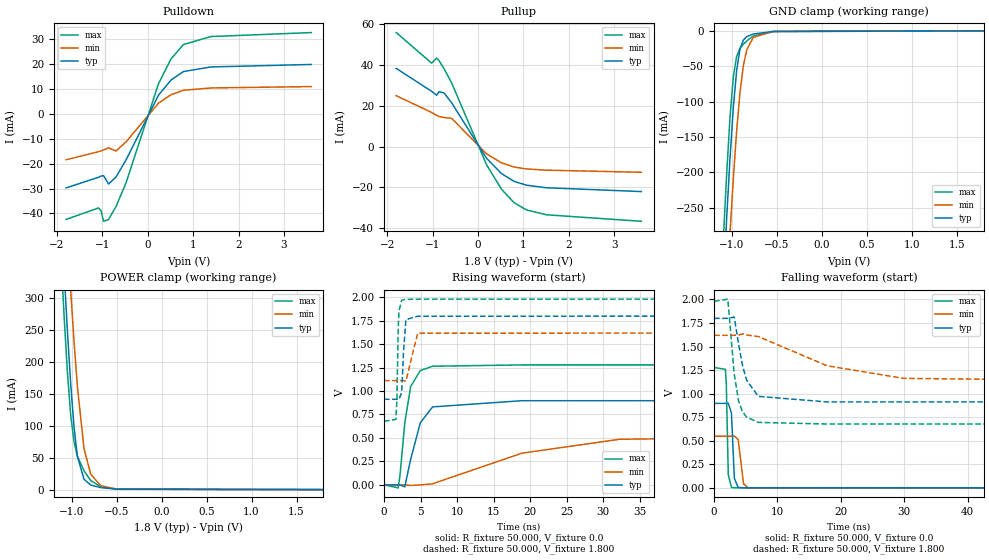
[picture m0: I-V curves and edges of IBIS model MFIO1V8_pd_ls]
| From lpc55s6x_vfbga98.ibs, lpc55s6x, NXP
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|   Model MFIO1V8_pd_ls
[Model] MFIO1V8_pd_ls
Model_type I/O
Polarity   Non-Inverting
Enable   Active-Low
Vinl =  0.540V
Vinh =  1.260V
Vmeas =  0.900V
Cref =  0.0F
Rref =  100.000
Vref =  0.0V
C_comp   2.019pF   1.989pF   2.027pF
C_comp_pullup   1.198pF   1.161pF   1.230pF
C_comp_pulldown   0.670pF   0.640pF   0.684pF
[Model Spec]
Vinh   1.260V   1.134V   1.386V
Vinl   0.540V   0.486V   0.594V
Vmeas   0.900V   0.810V   0.990V
Vref   0.0V   0.0V   0.0V
Cref   0.0F   0.0F   0.0F
Rref   100.000   100.000   100.000
[Temperature Range]   25.000   0.125k   -40.000
[Voltage Range]   1.800V   1.620V   1.980V
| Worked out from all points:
|   slope of the pulldown table from 0 to 0.27 V, typ, clamps not added: 32.2 ohm
|   slope of the pullup table from 0 to 0.27 V, typ, clamps not added: 34.3 ohm
|   GND clamp passes 1 mA (typ) near -0.56 V on its own axis
|   POWER clamp passes 1 mA (typ) near -0.54 V on its own axis
|   rising waveform, R_fixture 50.000, V_fixture 0.0: 20-80 % time 1.89ns typ, 15.8ns min, 1.21ns max; typ from 0 V to 0.897 V
|   rising waveform, R_fixture 50.000, V_fixture 1.800: 20-80 % time 276ps typ, 400ps min, 194ps max; typ from 0.912 V to 1.8 V
|   falling waveform, R_fixture 50.000, V_fixture 0.0: 20-80 % time 315ps typ, 493ps min, 217ps max; typ from 0.897 V to 0 V
|   falling waveform, R_fixture 50.000, V_fixture 1.800: 20-80 % time 1.84ns typ, 13.6ns min, 1.28ns max; typ from 1.8 V to 0.912 V
[Pulldown]
|Voltage   I(typ)   I(min)   I(max)
-1.8V     -29.75mA   -18.45mA   -42.39mA
-1.085V   -25.48mA   -15.2mA    -37.79mA
-1.03V    -24.99mA   -14.87mA   -38.88mA
-975mV    -24.83mA   -14.51mA   -43.15mA
-865mV    -28.18mA   -13.68mA   -42.43mA
-700mV    -25.38mA   -14.92mA   -37.23mA
-480mV    -18.54mA   -11.29mA   -27.73mA
235mV     7.474mA    4.265mA    12.03mA
510mV     13.55mA    7.648mA    22.01mA
785mV     16.96mA    9.446mA    27.8mA
1.39V     18.81mA    10.38mA    31.01mA
3.6V      19.8mA     10.93mA    32.61mA
[Pullup]
|Voltage   I(typ)   I(min)   I(max)
-1.8V     38.29mA    24.9mA     55.82mA
-1.02V    27.05mA    16.71mA    40.87mA
-910mV    25.14mA    15.31mA    43.32mA
-855mV    26.89mA    14.69mA    42.04mA
-745mV    26.24mA    14.22mA    38.06mA
-580mV    21.45mA    13.82mA    31.22mA
190mV     -5.761mA   -3.564mA   -8.914mA
520mV     -13.24mA   -7.997mA   -20.92mA
795mV     -17.02mA   -10.03mA   -27.47mA
1.07V     -18.92mA   -10.95mA   -31.04mA
1.51V     -20.18mA   -11.56mA   -33.41mA
3.6V      -22.04mA   -12.6mA    -36.6mA
[GND_clamp]
|Voltage   I(typ)   I(min)   I(max)
-1.8V     -2.463A    -2.494A    -2.446A
-1.097V   -357.7mA   -460.7mA   -294.8mA
-1.06V    -264.9mA   -370.9mA   -202.5mA
-1.023V   -180.4mA   -286.3mA   -122.9mA
-986mV    -108.7mA   -208.9mA   -65.05mA
-949mV    -56.06mA   -141.4mA   -36.24mA
-912mV    -25.87mA   -87.65mA   -25.01mA
-875mV    -13.21mA   -49.99mA   -19.06mA
-838mV    -8.315mA   -27.44mA   -14.52mA
-764mV    -4.558mA   -9.219mA   -7.395mA
-542mV    -813.9uA   -810.7uA   -1.086mA
1.8V      0A         0A         0A
[POWER_clamp]
|Voltage   I(typ)   I(min)   I(max)
-1.8V     2.577A     2.626A     2.553A
-1.123V   442.8mA    582.7mA    371.8mA
-1.086V   342mA      487.8mA    272.2mA
-1.049V   248.2mA    396.7mA    184.1mA
-1.012V   164.7mA    310.5mA    115.9mA
-975mV    97.4mA     231.2mA    74.47mA
-938mV    52.21mA    161.5mA    52.2mA
-864mV    16.15mA    64.06mA    29.43mA
-790mV    7.073mA    24.26mA    14.23mA
-679mV    3.152mA    6.087mA    4.407mA
-494mV    590.1uA    655.5uA    758.5uA
1.8V      0A         0A         0A
[Ramp]
| variable   typ   min   max
dV/dt_r   0.538/1.890n   0.328/15.774n   0.767/1.209n
dV/dt_f   0.532/1.835n   0.305/13.602n   0.781/1.275n
R_load = 50.000
[Rising Waveform]
R_fixture= 50.000
V_fixture= 0.0
V_fixture_min= 0.0
V_fixture_max= 0.0
|time   V(typ)   V(min)   V(max)
0s        6.721nV    117.6nV    4.416nV
1.96ns    159.2uV    49.14nV    -31.69mV
2.19ns    -99uV      -10.76uV   100.6mV
2.85ns    -21.07mV   112uV      661mV
3.65ns    271.3mV    -6.136mV   1.047V
4.97ns    661.3mV    -816.4uV   1.218V
6.65ns    830.9mV    11.84mV    1.264V
18.84ns   896.7mV    337.2mV    1.278V
32.24ns   896.7mV    486.1mV    1.278V
100ns     896.7mV    547.3mV    1.278V
[Rising Waveform]
R_fixture= 50.000
V_fixture= 1.800
V_fixture_min= 1.620
V_fixture_max= 1.980
|time   V(typ)   V(min)   V(max)
0s        911.9mV    1.111V     677.7mV
1.63ns    911.9mV    1.111V     697.7mV
1.77ns    912.1mV    1.111V     900.3mV
1.95ns    911.4mV    1.111V     1.665V
2.05ns    909.6mV    1.111V     1.849V
2.42ns    983.6mV    1.111V     1.967V
2.68ns    1.419V     1.11V      1.973V
3ns       1.76V      1.107V     1.976V
4.61ns    1.797V     1.616V     1.979V
100ns     1.799V     1.619V     1.979V
[Falling Waveform]
R_fixture= 50.000
V_fixture= 0.0
V_fixture_min= 0.0
V_fixture_max= 0.0
|time   V(typ)   V(min)   V(max)
0s        896.7mV    547.4mV    1.278V
1.79ns    896.7mV    547.4mV    1.258V
1.93ns    896.6mV    547.4mV    1.106V
2.24ns    898.4mV    547.4mV    142.2mV
2.74ns    796.7mV    547.3mV    4.509mV
3.2ns     100.7mV    549.7mV    1.658mV
3.81ns    3.552mV    513mV      778.9uV
4.65ns    1.171mV    43.83mV    345.8uV
5.32ns    655.7uV    1.786mV    189.7uV
100ns     14.3nV     184.2nV    8.877nV
[Falling Waveform]
R_fixture= 50.000
V_fixture= 1.800
V_fixture_min= 1.620
V_fixture_max= 1.980
|time   V(typ)   V(min)   V(max)
0s        1.799V     1.619V     1.979V
2.17ns    1.799V     1.619V     2.003V
3.18ns    1.813V     1.619V     1.21V
3.88ns    1.522V     1.623V     915.7mV
4.5ns     1.295V     1.633V     807.3mV
5.16ns    1.14V      1.622V     750mV
6.98ns    971mV      1.606V     694.9mV
17.82ns   912mV      1.296V     677.7mV
29.92ns   911.9mV    1.162V     677.7mV
100ns     911.9mV    1.111V     677.7mV
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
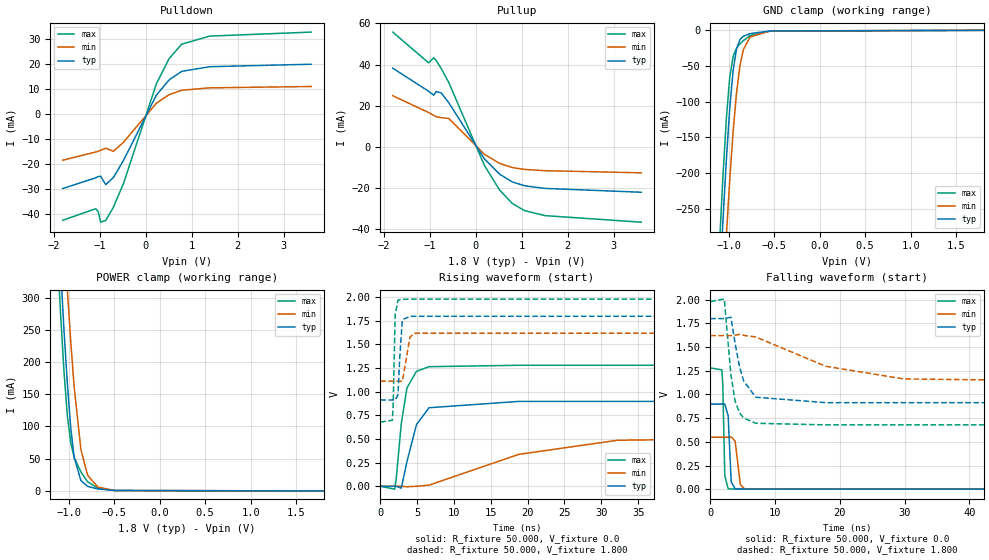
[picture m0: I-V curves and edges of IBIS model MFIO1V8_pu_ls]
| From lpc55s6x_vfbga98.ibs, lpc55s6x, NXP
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|   Model MFIO1V8_pu_ls
[Model] MFIO1V8_pu_ls
Model_type I/O
Polarity   Non-Inverting
Enable   Active-Low
Vinl =  0.540V
Vinh =  1.260V
Vmeas =  0.900V
Cref =  0.0F
Rref =  100.000
Vref =  0.0V
C_comp   2.019pF   1.989pF   2.027pF
C_comp_pullup   1.197pF   1.159pF   1.228pF
C_comp_pulldown   0.671pF   0.642pF   0.686pF
[Model Spec]
Vinh   1.260V   1.134V   1.386V
Vinl   0.540V   0.486V   0.594V
Vmeas   0.900V   0.810V   0.990V
Vref   0.0V   0.0V   0.0V
Cref   0.0F   0.0F   0.0F
Rref   100.000   100.000   100.000
[Temperature Range]   25.000   0.125k   -40.000
[Voltage Range]   1.800V   1.620V   1.980V
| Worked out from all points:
|   slope of the pulldown table from 0 to 0.27 V, typ, clamps not added: 32.2 ohm
|   slope of the pullup table from 0 to 0.27 V, typ, clamps not added: 34.3 ohm
|   GND clamp passes 1 mA (typ) near -0.56 V on its own axis
|   POWER clamp passes 1 mA (typ) near -0.54 V on its own axis
|   rising waveform, R_fixture 50.000, V_fixture 0.0: 20-80 % time 1.89ns typ, 15.8ns min, 1.21ns max; typ from 0.001 V to 0.898 V
|   rising waveform, R_fixture 50.000, V_fixture 1.800: 20-80 % time 275ps typ, 401ps min, 197ps max; typ from 0.913 V to 1.8 V
|   falling waveform, R_fixture 50.000, V_fixture 0.0: 20-80 % time 314ps typ, 502ps min, 216ps max; typ from 0.898 V to 0.001 V
|   falling waveform, R_fixture 50.000, V_fixture 1.800: 20-80 % time 1.84ns typ, 13.6ns min, 1.27ns max; typ from 1.8 V to 0.913 V
[Pulldown]
|Voltage   I(typ)   I(min)   I(max)
-1.8V     -29.75mA   -18.45mA   -42.39mA
-1.085V   -25.48mA   -15.2mA    -37.79mA
-1.03V    -24.99mA   -14.87mA   -38.88mA
-975mV    -24.83mA   -14.51mA   -43.15mA
-865mV    -28.18mA   -13.68mA   -42.43mA
-700mV    -25.38mA   -14.92mA   -37.23mA
-480mV    -18.54mA   -11.29mA   -27.73mA
235mV     7.474mA    4.265mA    12.03mA
510mV     13.55mA    7.648mA    22.01mA
785mV     16.96mA    9.446mA    27.8mA
1.39V     18.81mA    10.38mA    31.01mA
3.6V      19.8mA     10.93mA    32.61mA
[Pullup]
|Voltage   I(typ)   I(min)   I(max)
-1.8V     38.29mA    24.9mA     55.82mA
-1.02V    27.05mA    16.71mA    40.87mA
-910mV    25.14mA    15.31mA    43.32mA
-855mV    26.89mA    14.69mA    42.04mA
-745mV    26.24mA    14.22mA    38.06mA
-580mV    21.45mA    13.82mA    31.22mA
190mV     -5.761mA   -3.564mA   -8.914mA
520mV     -13.24mA   -7.997mA   -20.92mA
795mV     -17.02mA   -10.03mA   -27.47mA
1.07V     -18.92mA   -10.95mA   -31.04mA
1.51V     -20.18mA   -11.56mA   -33.41mA
3.6V      -22.04mA   -12.6mA    -36.6mA
[GND_clamp]
|Voltage   I(typ)   I(min)   I(max)
-1.8V     -2.463A    -2.494A    -2.446A
-1.097V   -357.7mA   -460.7mA   -294.9mA
-1.06V    -264.9mA   -371mA     -202.6mA
-1.023V   -180.4mA   -286.4mA   -122.9mA
-986mV    -108.7mA   -208.9mA   -65.09mA
-949mV    -56.09mA   -141.5mA   -36.28mA
-912mV    -25.91mA   -87.68mA   -25.06mA
-875mV    -13.24mA   -50.02mA   -19.11mA
-838mV    -8.35mA    -27.47mA   -14.57mA
-764mV    -4.593mA   -9.247mA   -7.441mA
-542mV    -849.5uA   -838.5uA   -1.132mA
1.8V      0A         0A         0A
[POWER_clamp]
|Voltage   I(typ)   I(min)   I(max)
-1.8V     2.577A     2.626A     2.553A
-1.123V   442.8mA    582.7mA    371.7mA
-1.086V   342mA      487.8mA    272.2mA
-1.049V   248.2mA    396.7mA    184.1mA
-1.012V   164.7mA    310.5mA    115.9mA
-975mV    97.36mA    231.1mA    74.42mA
-938mV    52.18mA    161.5mA    52.15mA
-864mV    16.11mA    64.03mA    29.39mA
-790mV    7.037mA    24.23mA    14.18mA
-679mV    3.116mA    6.059mA    4.361mA
-494mV    554.4uA    627.7uA    712.3uA
1.8V      0A         0A         0A
[Ramp]
| variable   typ   min   max
dV/dt_r   0.538/1.890n   0.329/15.774n   0.767/1.208n
dV/dt_f   0.532/1.835n   0.305/13.603n   0.781/1.276n
R_load = 50.000
[Rising Waveform]
R_fixture= 50.000
V_fixture= 0.0
V_fixture_min= 0.0
V_fixture_max= 0.0
|time   V(typ)   V(min)   V(max)
0s        630.6uV    679.1uV    587.5uV
1.96ns    789.2uV    679uV      -30.05mV
2.17ns    646.8uV    675.9uV    85.5mV
2.85ns    -19.7mV    790uV      661.1mV
3.62ns    261mV      -4.771mV   1.04V
4.91ns    652mV      527.3uV    1.216V
6.62ns    831mV      12.71mV    1.265V
18.81ns   898mV      338mV      1.28V
32.21ns   898mV      487.2mV    1.28V
100ns     898mV      548.5mV    1.28V
[Rising Waveform]
R_fixture= 50.000
V_fixture= 1.800
V_fixture_min= 1.620
V_fixture_max= 1.980
|time   V(typ)   V(min)   V(max)
0s        913.3mV    1.112V     678.9mV
1.63ns    913.3mV    1.112V     698.4mV
1.75ns    913.5mV    1.112V     853.9mV
2.02ns    911.7mV    1.112V     1.814V
2.4ns     967.4mV    1.112V     1.968V
2.67ns    1.397V     1.112V     1.974V
3ns       1.762V     1.109V     1.977V
4.03ns    1.797V     1.578V     1.979V
4.64ns    1.798V     1.618V     1.979V
100ns     1.8V       1.62V      1.98V
[Falling Waveform]
R_fixture= 50.000
V_fixture= 0.0
V_fixture_min= 0.0
V_fixture_max= 0.0
|time   V(typ)   V(min)   V(max)
0s        898mV      548.7mV    1.28V
1.79ns    898mV      548.7mV    1.259V
1.93ns    897.9mV    548.6mV    1.108V
2.24ns    899.8mV    548.7mV    143.9mV
2.76ns    775.9mV    548.5mV    5.275mV
3.23ns    78.56mV    551.3mV    2.369mV
3.84ns    4.35mV     507.6mV    1.439mV
4.64ns    1.976mV    49.12mV    976.3uV
5.28ns    1.396mV    3.386mV    806.1uV
100ns     630.7uV    679.2uV    587.5uV
[Falling Waveform]
R_fixture= 50.000
V_fixture= 1.800
V_fixture_min= 1.620
V_fixture_max= 1.980
|time   V(typ)   V(min)   V(max)
0s        1.8V       1.62V      1.98V
2.16ns    1.8V       1.62V      2.006V
3.18ns    1.814V     1.62V      1.212V
3.84ns    1.538V     1.623V     928.3mV
4.5ns     1.297V     1.634V     808mV
5.16ns    1.142V     1.623V     751.1mV
7.03ns    970.5mV    1.606V     695.5mV
17.83ns   913.4mV    1.297V     678.9mV
29.93ns   913.3mV    1.163V     678.9mV
100ns     913.3mV    1.112V     678.9mV
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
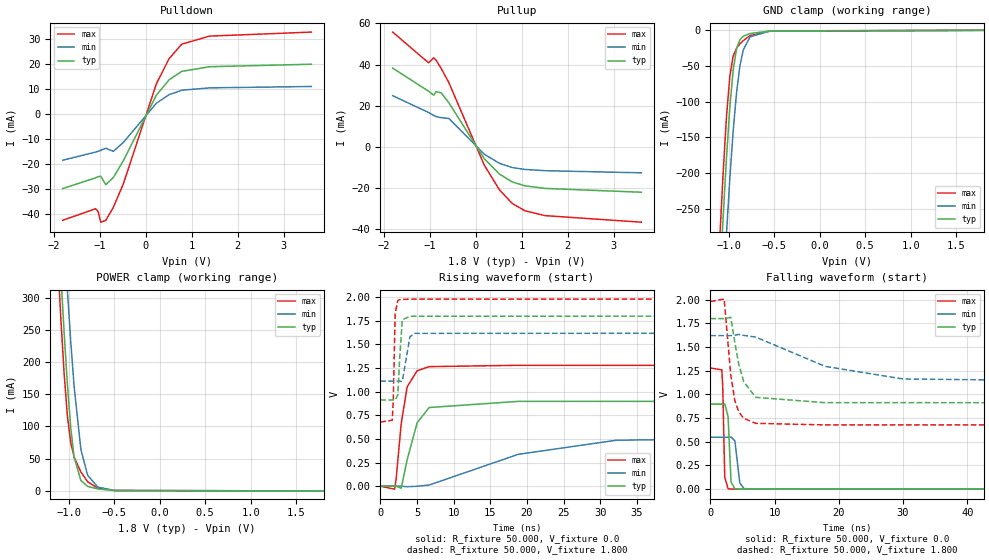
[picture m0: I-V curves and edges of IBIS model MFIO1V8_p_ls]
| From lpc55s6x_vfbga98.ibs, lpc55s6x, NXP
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|   Model MFIO1V8_p_ls
[Model] MFIO1V8_p_ls
Model_type I/O
Polarity   Non-Inverting
Enable   Active-Low
Vinl =  0.540V
Vinh =  1.260V
Vmeas =  0.900V
Cref =  0.0F
Rref =  100.000
Vref =  0.0V
C_comp   2.019pF   1.989pF   2.027pF
C_comp_pullup   1.197pF   1.160pF   1.229pF
C_comp_pulldown   0.671pF   0.641pF   0.686pF
[Model Spec]
Vinh   1.260V   1.134V   1.386V
Vinl   0.540V   0.486V   0.594V
Vmeas   0.900V   0.810V   0.990V
Vref   0.0V   0.0V   0.0V
Cref   0.0F   0.0F   0.0F
Rref   100.000   100.000   100.000
[Temperature Range]   25.000   0.125k   -40.000
[Voltage Range]   1.800V   1.620V   1.980V
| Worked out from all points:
|   slope of the pulldown table from 0 to 0.27 V, typ, clamps not added: 32.2 ohm
|   slope of the pullup table from 0 to 0.27 V, typ, clamps not added: 34.3 ohm
|   GND clamp passes 1 mA (typ) near -0.56 V on its own axis
|   POWER clamp passes 1 mA (typ) near -0.54 V on its own axis
|   rising waveform, R_fixture 50.000, V_fixture 0.0: 20-80 % time 1.89ns typ, 15.8ns min, 1.21ns max; typ from 0 V to 0.897 V
|   rising waveform, R_fixture 50.000, V_fixture 1.800: 20-80 % time 278ps typ, 404ps min, 192ps max; typ from 0.913 V to 1.8 V
|   falling waveform, R_fixture 50.000, V_fixture 0.0: 20-80 % time 314ps typ, 498ps min, 221ps max; typ from 0.897 V to 0 V
|   falling waveform, R_fixture 50.000, V_fixture 1.800: 20-80 % time 1.84ns typ, 13.6ns min, 1.28ns max; typ from 1.8 V to 0.913 V
[Pulldown]
|Voltage   I(typ)   I(min)   I(max)
-1.8V     -29.75mA   -18.45mA   -42.39mA
-1.085V   -25.48mA   -15.2mA    -37.79mA
-1.03V    -24.99mA   -14.87mA   -38.88mA
-975mV    -24.83mA   -14.51mA   -43.15mA
-865mV    -28.18mA   -13.68mA   -42.43mA
-700mV    -25.38mA   -14.92mA   -37.23mA
-480mV    -18.54mA   -11.29mA   -27.73mA
235mV     7.474mA    4.265mA    12.03mA
510mV     13.55mA    7.648mA    22.01mA
785mV     16.96mA    9.446mA    27.8mA
1.39V     18.81mA    10.38mA    31.01mA
3.6V      19.8mA     10.93mA    32.61mA
[Pullup]
|Voltage   I(typ)   I(min)   I(max)
-1.8V     38.29mA    24.9mA     55.82mA
-1.02V    27.05mA    16.71mA    40.87mA
-910mV    25.14mA    15.31mA    43.32mA
-855mV    26.89mA    14.69mA    42.04mA
-745mV    26.24mA    14.22mA    38.06mA
-580mV    21.45mA    13.82mA    31.22mA
190mV     -5.761mA   -3.564mA   -8.914mA
520mV     -13.24mA   -7.997mA   -20.92mA
795mV     -17.02mA   -10.03mA   -27.47mA
1.07V     -18.92mA   -10.95mA   -31.04mA
1.51V     -20.18mA   -11.56mA   -33.41mA
3.6V      -22.04mA   -12.6mA    -36.6mA
[GND_clamp]
|Voltage   I(typ)   I(min)   I(max)
-1.8V     -2.463A    -2.494A    -2.446A
-1.097V   -357.7mA   -460.7mA   -294.8mA
-1.06V    -264.9mA   -370.9mA   -202.5mA
-1.023V   -180.4mA   -286.3mA   -122.9mA
-986mV    -108.6mA   -208.9mA   -65.04mA
-949mV    -56.05mA   -141.4mA   -36.22mA
-912mV    -25.86mA   -87.64mA   -25mA
-875mV    -13.2mA    -49.98mA   -19.05mA
-838mV    -8.305mA   -27.43mA   -14.51mA
-764mV    -4.549mA   -9.211mA   -7.385mA
-542mV    -805.6uA   -803.8uA   -1.077mA
1.8V      0A         0A         0A
[POWER_clamp]
|Voltage   I(typ)   I(min)   I(max)
-1.8V     2.577A     2.626A     2.553A
-1.123V   442.8mA    582.7mA    371.7mA
-1.086V   342mA      487.8mA    272.1mA
-1.049V   248.2mA    396.6mA    184.1mA
-1.012V   164.7mA    310.5mA    115.9mA
-975mV    97.36mA    231.1mA    74.41mA
-938mV    52.17mA    161.5mA    52.14mA
-864mV    16.1mA     64.02mA    29.38mA
-790mV    7.028mA    24.22mA    14.17mA
-679mV    3.108mA    6.053mA    4.351mA
-494mV    546.6uA    621.4uA    702.9uA
1.8V      0A         0A         0A
[Ramp]
| variable   typ   min   max
dV/dt_r   0.538/1.892n   0.329/15.780n   0.768/1.210n
dV/dt_f   0.532/1.838n   0.305/13.606n   0.781/1.277n
R_load = 50.000
[Rising Waveform]
R_fixture= 50.000
V_fixture= 0.0
V_fixture_min= 0.0
V_fixture_max= 0.0
|time   V(typ)   V(min)   V(max)
0s        7.051nV    120nV      4.667nV
1.96ns    159.3uV    61.65nV    -31.77mV
2.17ns    23.61uV    -2.362uV   82.35mV
2.85ns    -21.07mV   111.7uV    659.8mV
3.66ns    277.4mV    -6.259mV   1.05V
5.02ns    670.7mV    -771.9uV   1.221V
6.67ns    832.3mV    12.22mV    1.265V
18.81ns   897.3mV    336.9mV    1.279V
32.21ns   897.3mV    486.3mV    1.279V
100ns     897.3mV    547.7mV    1.279V
[Rising Waveform]
R_fixture= 50.000
V_fixture= 1.800
V_fixture_min= 1.620
V_fixture_max= 1.980
|time   V(typ)   V(min)   V(max)
0s        912.6mV    1.112V     678.1mV
1.63ns    912.6mV    1.112V     697.9mV
1.77ns    912.8mV    1.112V     903.5mV
2.03ns    910.9mV    1.112V     1.828V
2.4ns     967.2mV    1.112V     1.967V
2.66ns    1.375V     1.111V     1.974V
3ns       1.761V     1.108V     1.977V
4.04ns    1.797V     1.58V      1.979V
4.66ns    1.798V     1.617V     1.979V
100ns     1.8V       1.62V      1.98V
[Falling Waveform]
R_fixture= 50.000
V_fixture= 0.0
V_fixture_min= 0.0
V_fixture_max= 0.0
|time   V(typ)   V(min)   V(max)
0s        897.3mV    547.8mV    1.279V
1.79ns    897.3mV    547.8mV    1.259V
1.94ns    897.2mV    547.8mV    1.082V
2.25ns    899.3mV    547.8mV    127mV
2.77ns    766mV      547.7mV    4.627mV
3.23ns    77.6mV     550.4mV    1.89mV
3.83ns    3.769mV    510mV      961.6uV
4.59ns    1.462mV    65.45mV    488.8uV
5.32ns    814.8uV    2.143mV    272.5uV
100ns     14.63nV    186.7nV    9.13nV
[Falling Waveform]
R_fixture= 50.000
V_fixture= 1.800
V_fixture_min= 1.620
V_fixture_max= 1.980
|time   V(typ)   V(min)   V(max)
0s        1.8V       1.62V      1.98V
2.16ns    1.8V       1.62V      2.006V
3.19ns    1.813V     1.62V      1.204V
3.83ns    1.543V     1.623V     931.6mV
4.44ns    1.316V     1.633V     815.6mV
5.2ns     1.135V     1.623V     748.4mV
7.07ns    968.8mV    1.605V     694.4mV
17.87ns   912.7mV    1.296V     678.1mV
29.97ns   912.6mV    1.163V     678.1mV
100ns     912.6mV    1.112V     678.1mV
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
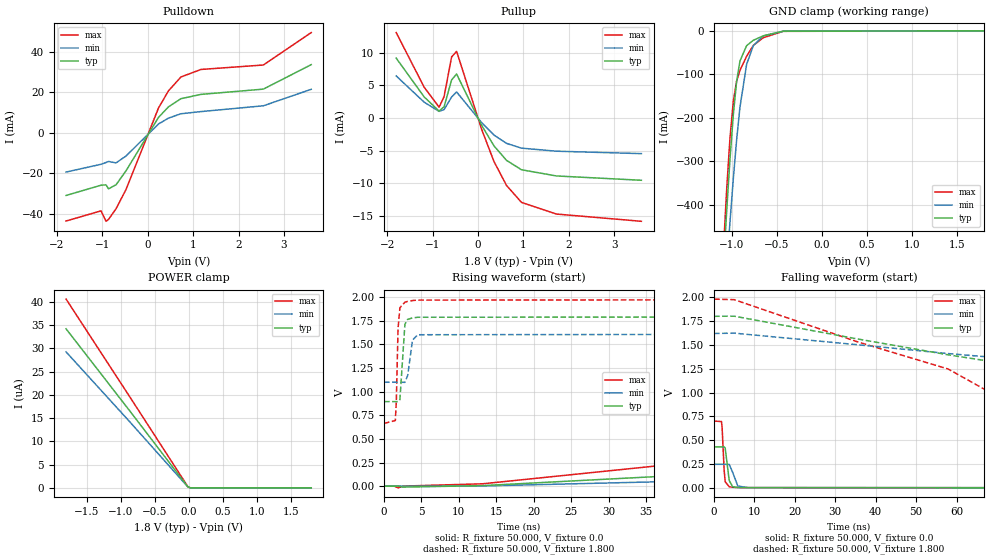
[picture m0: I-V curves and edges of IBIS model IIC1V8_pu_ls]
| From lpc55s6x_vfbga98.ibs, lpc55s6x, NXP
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|   Model IIC1V8_pu_ls
[Model] IIC1V8_pu_ls
Model_type I/O
Polarity   Non-Inverting
Enable   Active-Low
Vinl =  0.540V
Vinh =  1.260V
Vmeas =  0.900V
Cref =  0.0F
Rref =  100.000
Vref =  0.0V
C_comp   2.459pF   2.407pF   2.512pF
C_comp_pullup   0.441pF   0.385pF   0.517pF
C_comp_pulldown   1.692pF   1.593pF   1.772pF
[Model Spec]
Vinh   1.260V   1.134V   1.386V
Vinl   0.540V   0.486V   0.594V
Vmeas   0.900V   0.810V   0.990V
Vref   0.0V   0.0V   0.0V
Cref   0.0F   0.0F   0.0F
Rref   1000.000   1000.000   1000.000
[Temperature Range]   25.000   0.125k   -40.000
[Voltage Range]   1.800V   1.620V   1.980V
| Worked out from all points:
|   slope of the pulldown table from 0 to 0.27 V, typ, clamps not added: 31.5 ohm
|   slope of the pullup table from 0 to 0.27 V, typ, clamps not added: 79.6 ohm
|   GND clamp passes 1 mA (typ) near -0.44 V on its own axis
|   rising waveform, R_fixture 50.000, V_fixture 0.0: 20-80 % time 70.5ns typ, 79.7ns min, 57.9ns max; typ from 0.001 V to 0.425 V
|   rising waveform, R_fixture 50.000, V_fixture 1.800: 20-80 % time 332ps typ, 506ps min, 248ps max; typ from 0.895 V to 1.8 V
|   falling waveform, R_fixture 50.000, V_fixture 0.0: 20-80 % time 692ps typ, 1.08ns min, 490ps max; typ from 0.43 V to 0.001 V
|   falling waveform, R_fixture 50.000, V_fixture 1.800: 20-80 % time 66.5ns typ, 87.3ns min, 48.7ns max; typ from 1.8 V to 0.899 V
[Pulldown]
|Voltage   I(typ)   I(min)   I(max)
-1.8V     -30.97mA   -19.41mA   -43.61mA
-1.03V    -25.91mA   -15.56mA   -38.59mA
-920mV    -25.75mA   -14.67mA   -43.75mA
-865mV    -27.69mA   -14.16mA   -42.79mA
-700mV    -25.69mA   -14.87mA   -37.58mA
-480mV    -18.8mA    -11.48mA   -28.03mA
235mV     7.618mA    4.356mA    12.23mA
455mV     12.83mA    7.267mA    20.76mA
730mV     16.88mA    9.427mA    27.6mA
1.17V     19mA       10.49mA    31.33mA
2.545V    21.61mA    13.36mA    33.53mA
3.6V      33.71mA    21.52mA    49.57mA
[Pullup]
|Voltage   I(typ)   I(min)   I(max)
-1.8V     9.162mA    6.436mA    13.07mA
-1.185V   3.238mA    2.432mA    4.723mA
-855mV    1.061mA    1.015mA    1.659mA
-745mV    1.732mA    1.297mA    3.288mA
-580mV    5.824mA    3.207mA    9.344mA
-470mV    6.735mA    3.993mA    10.2mA
80mV      -1.101mA   -685.2uA   -1.694mA
355mV     -4.27mA    -2.612mA   -6.67mA
630mV     -6.475mA   -3.874mA   -10.31mA
960mV     -7.909mA   -4.605mA   -12.9mA
1.73V     -8.857mA   -5.07mA    -14.68mA
3.6V      -9.515mA   -5.442mA   -15.79mA
[GND_clamp]
|Voltage   I(typ)   I(min)   I(max)
-1.8V     -3.488A    -3.23A     -3.872A
-1.097V   -545.6mA   -658.5mA   -507.1mA
-1.06V    -414.6mA   -546.1mA   -365.1mA
-1.023V   -294.9mA   -439.1mA   -246mA
-986mV    -192.5mA   -339.6mA   -162mA
-949mV    -115.7mA   -250.4mA   -115.2mA
-912mV    -69.22mA   -175.3mA   -90.67mA
-838mV    -34.06mA   -77.19mA   -58.54mA
-764mV    -21.86mA   -34.13mA   -33.64mA
-653mV    -11.47mA   -11.68mA   -15.87mA
-431mV    -870uA     -906.4uA   -1.185mA
1.8V      0A         0A         0A
[POWER_clamp]
|Voltage   I(typ)   I(min)   I(max)
-1.8V     34.22uA    29.25uA    40.61uA
-864mV    16.54uA    14.2uA     19.57uA
-13mV     251.2nA    223.3nA    296.4nA
24mV      0A         0A         0A
1.8V      0A         0A         0A
[Ramp]
| variable   typ   min   max
dV/dt_r   0.255/70.462n   0.144/79.744n   0.419/57.898n
dV/dt_f   0.541/66.452n   0.308/87.295n   0.789/48.670n
R_load = 50.000
[Rising Waveform]
R_fixture= 50.000
V_fixture= 0.0
V_fixture_min= 0.0
V_fixture_max= 0.0
|time   V(typ)   V(min)   V(max)
0s        607.1uV    649.4uV    568.8uV
1.37ns    607.1uV    649.4uV    610.8uV
1.89ns    765.3uV    649.2uV    -18.16mV
2.53ns    -10.44mV   768.1uV    490.4uV
13.16ns   5.68mV     1.911mV    24.86mV
52.68ns   168.4mV    76.45mV    346.4mV
82.58ns   274.9mV    137.1mV    544.3mV
96.68ns   317.2mV    160mV      609mV
136.3ns   396.2mV    209.4mV    679.7mV
200ns     425.3mV    240.1mV    698.7mV
[Rising Waveform]
R_fixture= 50.000
V_fixture= 1.800
V_fixture_min= 1.620
V_fixture_max= 1.980
|time   V(typ)   V(min)   V(max)
0s        895.1mV    1.1V       664.1mV
1.52ns    895.1mV    1.1V       694.3mV
1.65ns    895.2mV    1.1V       890.1mV
1.88ns    894.5mV    1.1V       1.667V
2.13ns    916.4mV    1.1V       1.889V
2.8ns     1.715V     1.099V     1.947V
3.17ns    1.766V     1.172V     1.956V
3.81ns    1.781V     1.545V     1.965V
4.5ns     1.788V     1.603V     1.97V
200ns     1.8V       1.62V      1.98V
[Falling Waveform]
R_fixture= 50.000
V_fixture= 0.0
V_fixture_min= 0.0
V_fixture_max= 0.0
|time   V(typ)   V(min)   V(max)
0s        430.3mV    247.6mV    701.2mV
1.83ns    430.3mV    247.6mV    695.9mV
1.98ns    430.3mV    247.6mV    638.1mV
2.5ns     431.3mV    247.6mV    181.3mV
2.75ns    417.9mV    247.6mV    65.43mV
3.74ns    77.58mV    247.1mV    12.39mV
4.6ns     11.9mV     163mV      6.764mV
5.87ns    4.599mV    20.21mV    4.361mV
8.34ns    2.518mV    2.716mV    3.324mV
200ns     607.5uV    650.2uV    568.9uV
[Falling Waveform]
R_fixture= 50.000
V_fixture= 1.800
V_fixture_min= 1.620
V_fixture_max= 1.980
|time   V(typ)   V(min)   V(max)
0s        1.8V       1.62V      1.98V
5.02ns    1.801V     1.623V     1.974V
35.41ns   1.563V     1.502V     1.533V
57.9ns    1.396V     1.409V     1.247V
71.61ns   1.306V     1.36V      923.3mV
85.06ns   1.187V     1.317V     777mV
100.5ns   1.038V     1.271V     712.9mV
120.6ns   953.8mV    1.204V     682.3mV
151.2ns   912.7mV    1.133V     668.8mV
200ns     898.6mV    1.106V     665mV
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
